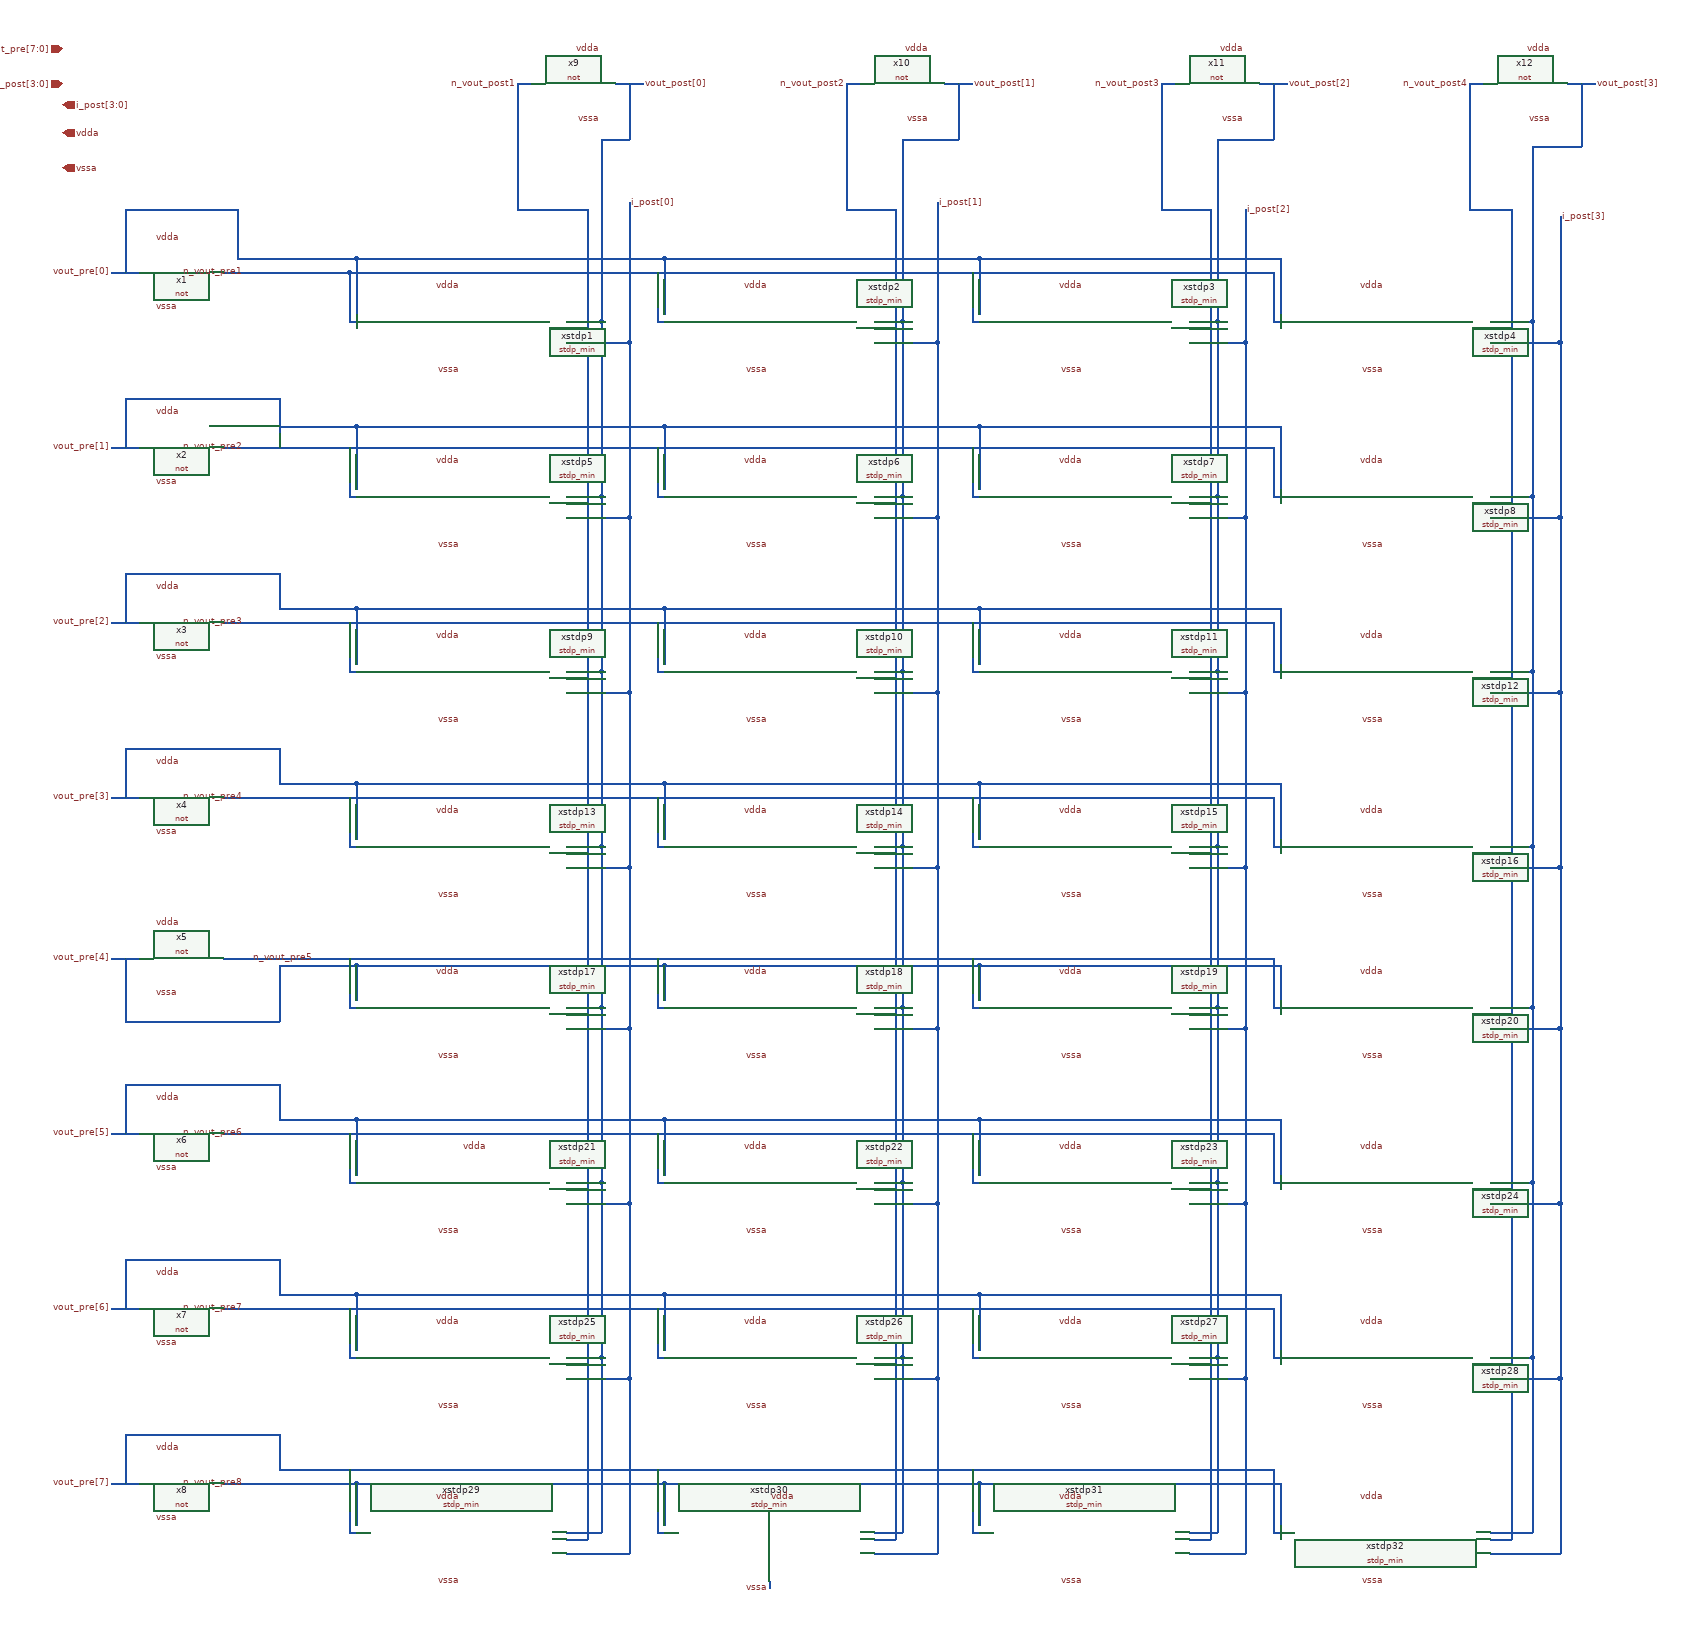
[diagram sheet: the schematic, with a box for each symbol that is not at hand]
v {xschem version=3.4.8RC file_version=1.3}
G {}
K {}
V {}
S {}
F {}
E {}
N 1130 110 1130 200 {
lab=n_vout_pre2}
N 700 110 1130 110 {
lab=n_vout_pre2}
N 1130 620 1130 700 {
lab=n_vout_pre4}
N 700 620 1130 620 {
lab=n_vout_pre4}
N 700 370 1130 370 {
lab=n_vout_pre3}
N 1130 370 1130 450 {
lab=n_vout_pre3}
N 700 110 700 200 {
lab=n_vout_pre2}
N 250 110 250 200 {
lab=n_vout_pre2}
N -190 110 -190 200 {
lab=n_vout_pre2}
N -190 370 -190 450 {
lab=n_vout_pre3}
N 250 370 250 450 {
lab=n_vout_pre3}
N 700 370 700 450 {
lab=n_vout_pre3}
N -190 620 -190 700 {
lab=n_vout_pre4}
N 250 620 250 700 {
lab=n_vout_pre4}
N 700 620 700 700 {
lab=n_vout_pre4}
N 160 460 160 710 {
lab=vout_post[0]}
N 110 710 160 710 {
lab=vout_post[0]}
N 110 460 160 460 {
lab=vout_post[0]}
N 110 210 160 210 {
lab=vout_post[0]}
N 110 -40 160 -40 {
lab=vout_post[0]}
N 590 460 590 710 {
lab=vout_post[1]}
N 550 710 590 710 {
lab=vout_post[1]}
N 550 460 590 460 {
lab=vout_post[1]}
N 550 210 590 210 {
lab=vout_post[1]}
N 550 -40 590 -40 {
lab=vout_post[1]}
N 1040 460 1040 710 {
lab=vout_post[2]}
N 1000 710 1040 710 {
lab=vout_post[2]}
N 1000 460 1040 460 {
lab=vout_post[2]}
N 1000 210 1040 210 {
lab=vout_post[2]}
N 1000 -40 1040 -40 {
lab=vout_post[2]}
N 1490 460 1490 710 {
lab=vout_post[3]}
N 1430 710 1490 710 {
lab=vout_post[3]}
N 1430 460 1490 460 {
lab=vout_post[3]}
N 1430 -40 1490 -40 {
lab=vout_post[3]}
N 200 490 200 740 {
lab=i_post[0]}
N 110 740 200 740 {
lab=i_post[0]}
N 110 -10 200 -10 {
lab=i_post[0]}
N 110 240 200 240 {
lab=i_post[0]}
N 110 490 200 490 {
lab=i_post[0]}
N 640 490 640 740 {
lab=i_post[1]}
N 550 740 640 740 {
lab=i_post[1]}
N 550 490 640 490 {
lab=i_post[1]}
N 550 240 640 240 {
lab=i_post[1]}
N 550 -10 640 -10 {
lab=i_post[1]}
N 1080 490 1080 740 {
lab=i_post[2]}
N 1000 740 1080 740 {
lab=i_post[2]}
N 1000 490 1080 490 {
lab=i_post[2]}
N 1000 240 1080 240 {
lab=i_post[2]}
N 1000 -10 1080 -10 {
lab=i_post[2]}
N 1530 490 1530 740 {
lab=i_post[3]}
N 1430 740 1530 740 {
lab=i_post[3]}
N 1430 490 1530 490 {
lab=i_post[3]}
N 1430 -10 1530 -10 {
lab=i_post[3]}
N 160 1440 160 1690 {
lab=vout_post[0]}
N 160 710 160 940 {
lab=vout_post[0]}
N 590 1440 590 1690 {
lab=vout_post[1]}
N 590 710 590 940 {
lab=vout_post[1]}
N 1040 1440 1040 1690 {
lab=vout_post[2]}
N 1040 710 1040 940 {
lab=vout_post[2]}
N 1490 1440 1490 1690 {
lab=vout_post[3]}
N 1490 710 1490 940 {
lab=vout_post[3]}
N 200 1470 200 1720 {
lab=i_post[0]}
N 110 1720 200 1720 {
lab=i_post[0]}
N 640 1470 640 1720 {
lab=i_post[1]}
N 1080 1470 1080 1720 {
lab=i_post[2]}
N 1530 1470 1530 1720 {
lab=i_post[3]}
N 110 940 160 940 {
lab=vout_post[0]}
N 110 970 200 970 {
lab=i_post[0]}
N 110 1190 160 1190 {
lab=vout_post[0]}
N 110 1220 200 1220 {
lab=i_post[0]}
N 110 1440 160 1440 {
lab=vout_post[0]}
N 110 1470 200 1470 {
lab=i_post[0]}
N 110 1690 160 1690 {
lab=vout_post[0]}
N 550 1690 590 1690 {
lab=vout_post[1]}
N 550 1720 640 1720 {
lab=i_post[1]}
N 550 1440 590 1440 {
lab=vout_post[1]}
N 550 1470 640 1470 {
lab=i_post[1]}
N 550 1190 590 1190 {
lab=vout_post[1]}
N 550 1220 640 1220 {
lab=i_post[1]}
N 550 940 590 940 {
lab=vout_post[1]}
N 550 970 640 970 {
lab=i_post[1]}
N 1000 940 1040 940 {
lab=vout_post[2]}
N 1000 970 1080 970 {
lab=i_post[2]}
N 1000 1190 1040 1190 {
lab=vout_post[2]}
N 1000 1220 1080 1220 {
lab=i_post[2]}
N 1000 1440 1040 1440 {
lab=vout_post[2]}
N 1000 1470 1080 1470 {
lab=i_post[2]}
N 1000 1690 1040 1690 {
lab=vout_post[2]}
N 1000 1720 1080 1720 {
lab=i_post[2]}
N 1430 1690 1490 1690 {
lab=vout_post[3]}
N 1430 1720 1530 1720 {
lab=i_post[3]}
N 1430 1440 1490 1440 {
lab=vout_post[3]}
N 1430 1470 1530 1470 {
lab=i_post[3]}
N 1430 1190 1490 1190 {
lab=vout_post[3]}
N 1430 1220 1530 1220 {
lab=i_post[3]}
N 1430 940 1490 940 {
lab=vout_post[3]}
N 1430 970 1530 970 {
lab=i_post[3]}
N 700 880 1130 880 {
lab=n_vout_pre5}
N -190 880 -190 930 {
lab=n_vout_pre5}
N 250 880 250 930 {
lab=n_vout_pre5}
N 700 880 700 930 {
lab=n_vout_pre5}
N 1130 880 1130 930 {
lab=n_vout_pre5}
N 700 1100 1130 1100 {
lab=n_vout_pre6}
N -190 1100 -190 1180 {
lab=n_vout_pre6}
N 250 1100 250 1180 {
lab=n_vout_pre6}
N 700 1100 700 1180 {
lab=n_vout_pre6}
N 1130 1100 1130 1180 {
lab=n_vout_pre6}
N 700 1350 1130 1350 {
lab=n_vout_pre7}
N -190 1350 -190 1430 {
lab=n_vout_pre7}
N 250 1350 250 1430 {
lab=n_vout_pre7}
N 700 1350 700 1430 {
lab=n_vout_pre7}
N 1130 1350 1130 1430 {
lab=n_vout_pre7}
N 700 1620 1130 1620 {
lab=n_vout_pre8}
N -190 1620 -190 1680 {
lab=n_vout_pre8}
N 250 1620 250 1680 {
lab=n_vout_pre8}
N 700 1620 700 1680 {
lab=n_vout_pre8}
N 1130 1620 1130 1680 {
lab=n_vout_pre8}
N 400 1760 400 1770 {
lab=vssa}
N 700 -130 1130 -130 {lab=vout_pre[0]}
N 1430 210 1490 210 {lab=vout_post[3]}
N 1430 240 1530 240 {lab=i_post[3]}
N -190 -130 250 -130 {lab=vout_pre[0]}
N 250 -130 700 -130 {lab=vout_pre[0]}
N 250 110 700 110 {
lab=n_vout_pre2}
N -190 110 250 110 {
lab=n_vout_pre2}
N -300 110 -190 110 {
lab=n_vout_pre2}
N -300 370 -190 370 {
lab=n_vout_pre3}
N -190 370 250 370 {
lab=n_vout_pre3}
N 250 370 700 370 {
lab=n_vout_pre3}
N -300 620 -190 620 {
lab=n_vout_pre4}
N -190 620 250 620 {
lab=n_vout_pre4}
N 250 620 700 620 {
lab=n_vout_pre4}
N 160 210 160 460 {
lab=vout_post[0]}
N 160 -40 160 210 {
lab=vout_post[0]}
N 160 -200 160 -40 {
lab=vout_post[0]}
N 590 210 590 460 {
lab=vout_post[1]}
N 590 -40 590 210 {
lab=vout_post[1]}
N 590 -200 590 -40 {
lab=vout_post[1]}
N 1040 210 1040 460 {
lab=vout_post[2]}
N 1040 -40 1040 210 {
lab=vout_post[2]}
N 1040 -190 1040 -40 {
lab=vout_post[2]}
N 1490 210 1490 460 {
lab=vout_post[3]}
N 1490 -180 1490 -40 {
lab=vout_post[3]}
N 200 -210 200 -10 {
lab=i_post[0]}
N 200 -10 200 240 {
lab=i_post[0]}
N 200 240 200 490 {
lab=i_post[0]}
N 640 240 640 490 {
lab=i_post[1]}
N 640 -10 640 240 {
lab=i_post[1]}
N 640 -210 640 -10 {
lab=i_post[1]}
N 1080 240 1080 490 {
lab=i_post[2]}
N 1080 -10 1080 240 {
lab=i_post[2]}
N 1080 -200 1080 -10 {
lab=i_post[2]}
N 1530 240 1530 490 {
lab=i_post[3]}
N 1530 -190 1530 -10 {
lab=i_post[3]}
N 200 740 200 970 {
lab=i_post[0]}
N 160 940 160 1190 {
lab=vout_post[0]}
N 200 970 200 1220 {
lab=i_post[0]}
N 160 1190 160 1440 {
lab=vout_post[0]}
N 200 1220 200 1470 {
lab=i_post[0]}
N 590 1190 590 1440 {
lab=vout_post[1]}
N 640 1220 640 1470 {
lab=i_post[1]}
N 590 940 590 1190 {
lab=vout_post[1]}
N 640 970 640 1220 {
lab=i_post[1]}
N 640 740 640 970 {
lab=i_post[1]}
N 1080 740 1080 970 {
lab=i_post[2]}
N 1040 940 1040 1190 {
lab=vout_post[2]}
N 1080 970 1080 1220 {
lab=i_post[2]}
N 1040 1190 1040 1440 {
lab=vout_post[2]}
N 1080 1220 1080 1470 {
lab=i_post[2]}
N 1490 1190 1490 1440 {
lab=vout_post[3]}
N 1530 1220 1530 1470 {
lab=i_post[3]}
N 1490 940 1490 1190 {
lab=vout_post[3]}
N 1530 970 1530 1220 {
lab=i_post[3]}
N 1530 740 1530 970 {
lab=i_post[3]}
N -300 880 -190 880 {
lab=n_vout_pre5}
N -190 880 250 880 {
lab=n_vout_pre5}
N 250 880 700 880 {
lab=n_vout_pre5}
N -300 1100 -190 1100 {
lab=n_vout_pre6}
N -190 1100 250 1100 {
lab=n_vout_pre6}
N 250 1100 700 1100 {
lab=n_vout_pre6}
N -300 1350 -190 1350 {
lab=n_vout_pre7}
N -190 1350 250 1350 {
lab=n_vout_pre7}
N 250 1350 700 1350 {
lab=n_vout_pre7}
N -300 1620 -190 1620 {
lab=n_vout_pre8}
N -190 1620 250 1620 {
lab=n_vout_pre8}
N 250 1620 700 1620 {
lab=n_vout_pre8}
N 1490 -40 1490 210 {
lab=vout_post[3]}
N 1530 -10 1530 240 {
lab=i_post[3]}
N -200 -110 -200 -40 {lab=vout_pre[0]}
N -200 -40 -190 -40 {lab=vout_pre[0]}
N 1120 -40 1130 -40 {lab=vout_pre[0]}
N 1120 -110 1120 -40 {lab=vout_pre[0]}
N 690 -40 700 -40 {lab=vout_pre[0]}
N 690 -110 690 -40 {lab=vout_pre[0]}
N 240 -40 250 -40 {lab=vout_pre[0]}
N 240 -110 240 -40 {lab=vout_pre[0]}
N -200 140 -200 210 {lab=n_vout_pre2}
N -200 210 -190 210 {lab=n_vout_pre2}
N -300 140 1120 140 {lab=n_vout_pre2}
N 1120 210 1130 210 {lab=n_vout_pre2}
N 1120 140 1120 210 {lab=n_vout_pre2}
N 690 210 700 210 {lab=n_vout_pre2}
N 690 140 690 210 {lab=n_vout_pre2}
N 240 210 250 210 {lab=n_vout_pre2}
N 240 140 240 210 {lab=n_vout_pre2}
N -200 390 -200 460 {lab=n_vout_pre3}
N -200 460 -190 460 {lab=n_vout_pre3}
N -300 390 1120 390 {lab=n_vout_pre3}
N 1120 460 1130 460 {lab=n_vout_pre3}
N 1120 390 1120 460 {lab=n_vout_pre3}
N 690 460 700 460 {lab=n_vout_pre3}
N 690 390 690 460 {lab=n_vout_pre3}
N 240 460 250 460 {lab=n_vout_pre3}
N 240 390 240 460 {lab=n_vout_pre3}
N -200 640 -200 710 {lab=n_vout_pre4}
N -200 710 -190 710 {lab=n_vout_pre4}
N -300 640 1120 640 {lab=n_vout_pre4}
N 1120 710 1130 710 {lab=n_vout_pre4}
N 1120 640 1120 710 {lab=n_vout_pre4}
N 690 710 700 710 {lab=n_vout_pre4}
N 690 640 690 710 {lab=n_vout_pre4}
N 240 710 250 710 {lab=n_vout_pre4}
N 240 640 240 710 {lab=n_vout_pre4}
N -200 870 -200 940 {lab=n_vout_pre5}
N -200 940 -190 940 {lab=n_vout_pre5}
N -300 870 1120 870 {lab=n_vout_pre5}
N 1120 940 1130 940 {lab=n_vout_pre5}
N 1120 870 1120 940 {lab=n_vout_pre5}
N 690 940 700 940 {lab=n_vout_pre5}
N 690 870 690 940 {lab=n_vout_pre5}
N 240 940 250 940 {lab=n_vout_pre5}
N 240 870 240 940 {lab=n_vout_pre5}
N -200 1120 -200 1190 {lab=n_vout_pre6}
N -200 1190 -190 1190 {lab=n_vout_pre6}
N -300 1120 1120 1120 {lab=n_vout_pre6}
N 1120 1190 1130 1190 {lab=n_vout_pre6}
N 1120 1120 1120 1190 {lab=n_vout_pre6}
N 690 1190 700 1190 {lab=n_vout_pre6}
N 690 1120 690 1190 {lab=n_vout_pre6}
N 240 1190 250 1190 {lab=n_vout_pre6}
N 240 1120 240 1190 {lab=n_vout_pre6}
N -200 1370 -200 1440 {lab=n_vout_pre7}
N -200 1440 -190 1440 {lab=n_vout_pre7}
N -300 1370 1120 1370 {lab=n_vout_pre7}
N 1120 1440 1130 1440 {lab=n_vout_pre7}
N 1120 1370 1120 1440 {lab=n_vout_pre7}
N 690 1440 700 1440 {lab=n_vout_pre7}
N 690 1370 690 1440 {lab=n_vout_pre7}
N 240 1440 250 1440 {lab=n_vout_pre7}
N 240 1370 240 1440 {lab=n_vout_pre7}
N -300 1600 1120 1600 {lab=n_vout_pre8}
N -200 1690 -190 1690 {lab=n_vout_pre8}
N -200 1640 -200 1690 {lab=n_vout_pre8}
N 240 1690 250 1690 {lab=n_vout_pre8}
N -200 1600 -200 1640 {lab=n_vout_pre8}
N 240 1600 240 1690 {lab=n_vout_pre8}
N 690 1690 700 1690 {lab=n_vout_pre8}
N 690 1600 690 1690 {lab=n_vout_pre8}
N 1120 1690 1130 1690 {lab=n_vout_pre8}
N 1120 1600 1120 1690 {lab=n_vout_pre8}
N -540 -110 -500 -110 {lab=vout_pre[0]}
N -380 -110 -350 -110 {lab=vout_pre[0]}
N -540 140 -500 140 {lab=n_vout_pre2}
N -380 140 -350 140 {lab=n_vout_pre2}
N -350 140 -300 140 {lab=n_vout_pre2}
N -520 70 -520 140 {lab=n_vout_pre2}
N -300 70 -300 120 {lab=n_vout_pre2}
N -520 70 -300 70 {lab=n_vout_pre2}
N -540 390 -500 390 {lab=n_vout_pre3}
N -380 390 -350 390 {lab=n_vout_pre3}
N -350 390 -300 390 {lab=n_vout_pre3}
N -520 320 -520 390 {lab=n_vout_pre3}
N -520 320 -300 320 {lab=n_vout_pre3}
N -300 320 -300 370 {lab=n_vout_pre3}
N -540 640 -500 640 {lab=n_vout_pre4}
N -380 640 -350 640 {lab=n_vout_pre4}
N -520 570 -520 640 {lab=n_vout_pre4}
N -520 570 -300 570 {lab=n_vout_pre4}
N -300 570 -300 620 {lab=n_vout_pre4}
N -350 640 -300 640 {lab=n_vout_pre4}
N -540 870 -500 870 {lab=n_vout_pre5}
N -380 870 -350 870 {lab=n_vout_pre5}
N -350 870 -300 870 {lab=n_vout_pre5}
N -300 880 -300 960 {lab=n_vout_pre5}
N -520 960 -300 960 {lab=n_vout_pre5}
N -520 870 -520 960 {lab=n_vout_pre5}
N -540 1120 -500 1120 {lab=n_vout_pre6}
N -380 1120 -350 1120 {lab=n_vout_pre6}
N -520 1050 -520 1120 {lab=n_vout_pre6}
N -520 1050 -300 1050 {lab=n_vout_pre6}
N -350 1120 -300 1120 {lab=n_vout_pre6}
N -300 1050 -300 1100 {lab=n_vout_pre6}
N -540 1370 -500 1370 {lab=n_vout_pre7}
N -380 1370 -350 1370 {lab=n_vout_pre7}
N -520 1300 -520 1370 {lab=n_vout_pre7}
N -520 1300 -300 1300 {lab=n_vout_pre7}
N -350 1370 -300 1370 {lab=n_vout_pre7}
N -300 1300 -300 1350 {lab=n_vout_pre7}
N -540 1620 -500 1620 {lab=n_vout_pre8}
N -380 1620 -350 1620 {lab=n_vout_pre8}
N -520 1550 -520 1620 {lab=n_vout_pre8}
N -520 1550 -300 1550 {lab=n_vout_pre8}
N -350 1620 -300 1620 {lab=n_vout_pre8}
N -300 1550 -300 1600 {lab=n_vout_pre8}
N 140 -200 140 1700 {lab=n_vout_post1}
N 110 1700 140 1700 {lab=n_vout_post1}
N 110 1450 140 1450 {lab=n_vout_post1}
N 110 1200 140 1200 {lab=n_vout_post1}
N 110 950 140 950 {lab=n_vout_post1}
N 110 720 140 720 {lab=n_vout_post1}
N 110 470 140 470 {lab=n_vout_post1}
N 110 220 140 220 {lab=n_vout_post1}
N 110 -30 140 -30 {lab=n_vout_post1}
N 580 -200 580 1700 {lab=n_vout_post2}
N 550 1700 580 1700 {lab=n_vout_post2}
N 550 1450 580 1450 {lab=n_vout_post2}
N 550 1200 580 1200 {lab=n_vout_post2}
N 550 950 580 950 {lab=n_vout_post2}
N 550 720 580 720 {lab=n_vout_post2}
N 550 470 580 470 {lab=n_vout_post2}
N 550 220 580 220 {lab=n_vout_post2}
N 550 -30 580 -30 {lab=n_vout_post2}
N 1030 -200 1030 1700 {lab=n_vout_post3}
N 1000 1700 1030 1700 {lab=n_vout_post3}
N 1000 1450 1030 1450 {lab=n_vout_post3}
N 1000 1200 1030 1200 {lab=n_vout_post3}
N 1000 950 1030 950 {lab=n_vout_post3}
N 1000 720 1030 720 {lab=n_vout_post3}
N 1000 470 1030 470 {lab=n_vout_post3}
N 1000 220 1030 220 {lab=n_vout_post3}
N 1000 -30 1030 -30 {lab=n_vout_post3}
N 1460 -200 1460 1700 {lab=n_vout_post4}
N 1430 1700 1460 1700 {lab=n_vout_post4}
N 1430 1450 1460 1450 {lab=n_vout_post4}
N 1430 1200 1460 1200 {lab=n_vout_post4}
N 1430 950 1460 950 {lab=n_vout_post4}
N 1430 720 1460 720 {lab=n_vout_post4}
N 1430 470 1460 470 {lab=n_vout_post4}
N 1430 220 1460 220 {lab=n_vout_post4}
N 1430 -30 1460 -30 {lab=n_vout_post4}
N 180 -380 220 -380 {lab=vout_post[0]}
N 40 -380 60 -380 {lab=n_vout_post1}
N 40 -380 40 -200 {lab=n_vout_post1}
N 40 -200 140 -200 {lab=n_vout_post1}
N 160 -300 160 -200 {lab=vout_post[0]}
N 160 -300 200 -300 {lab=vout_post[0]}
N 200 -380 200 -300 {lab=vout_post[0]}
N 650 -380 690 -380 {lab=vout_post[1]}
N 510 -380 530 -380 {lab=n_vout_post2}
N 510 -380 510 -200 {lab=n_vout_post2}
N 670 -380 670 -300 {lab=vout_post[1]}
N 590 -300 670 -300 {lab=vout_post[1]}
N 590 -300 590 -200 {lab=vout_post[1]}
N 510 -200 580 -200 {lab=n_vout_post2}
N 1100 -380 1140 -380 {lab=vout_post[2]}
N 960 -380 980 -380 {lab=n_vout_post3}
N 960 -380 960 -200 {lab=n_vout_post3}
N 1120 -380 1120 -300 {lab=vout_post[2]}
N 960 -200 1030 -200 {lab=n_vout_post3}
N 1040 -300 1040 -190 {lab=vout_post[2]}
N 1040 -300 1120 -300 {lab=vout_post[2]}
N 1540 -380 1580 -380 {lab=vout_post[3]}
N 1400 -380 1420 -380 {lab=n_vout_post4}
N 1400 -380 1400 -200 {lab=n_vout_post4}
N 1560 -380 1560 -300 {lab=vout_post[3]}
N 1410 -200 1460 -200 {lab=n_vout_post4}
N 1490 -290 1490 -180 {lab=vout_post[3]}
N 1490 -290 1560 -290 {lab=vout_post[3]}
N 1560 -300 1560 -290 {lab=vout_post[3]}
N 1400 -200 1410 -200 {lab=n_vout_post4}
N -190 -130 -190 -50 {lab=vout_pre[0]}
N -200 -110 1120 -110 {lab=vout_pre[0]}
N 250 -130 250 -50 {lab=vout_pre[0]}
N 700 -130 700 -50 {lab=vout_pre[0]}
N 1130 -130 1130 -50 {lab=vout_pre[0]}
N -350 -110 -200 -110 {lab=vout_pre[0]}
N -360 -130 -190 -130 {lab=vout_pre[0]}
N -360 -200 -360 -130 {lab=vout_pre[0]}
N -520 -200 -360 -200 {lab=vout_pre[0]}
N -520 -200 -520 -110 {lab=vout_pre[0]}
C {devices/lab_pin.sym} -540 -110 0 0 {name=p1 lab=vout_pre[0]}
C {devices/iopin.sym} -610 -310 0 1 {name=p7 lab=vdda}
C {devices/iopin.sym} -610 -260 0 1 {name=p8 lab=vssa}
C {Synapse/stdp_min.sym} 400 -50 0 0 {name=xstdp2}
C {Synapse/stdp_min.sym} 850 -50 0 0 {name=xstdp3}
C {Synapse/stdp_min.sym} 1280 -50 0 0 {name=xstdp4}
C {devices/lab_pin.sym} 200 -210 0 1 {name=p9 lab=i_post[0]}
C {Synapse/stdp_min.sym} -40 200 0 0 {name=xstdp5}
C {Synapse/stdp_min.sym} 400 200 0 0 {name=xstdp6}
C {Synapse/stdp_min.sym} 850 200 0 0 {name=xstdp7}
C {Synapse/stdp_min.sym} 1280 200 0 0 {name=xstdp8}
C {Synapse/stdp_min.sym} -40 450 0 0 {name=xstdp9}
C {Synapse/stdp_min.sym} 400 450 0 0 {name=xstdp10}
C {Synapse/stdp_min.sym} 850 450 0 0 {name=xstdp11}
C {Synapse/stdp_min.sym} 1280 450 0 0 {name=xstdp12}
C {Synapse/stdp_min.sym} -40 700 0 0 {name=xstdp13}
C {Synapse/stdp_min.sym} 400 700 0 0 {name=xstdp14}
C {Synapse/stdp_min.sym} 850 700 0 0 {name=xstdp15}
C {Synapse/stdp_min.sym} 1280 700 0 0 {name=xstdp16}
C {devices/lab_pin.sym} -40 -90 1 0 {name=p20 sig_type=std_logic lab=vdda}
C {devices/lab_pin.sym} -40 160 1 0 {name=p21 sig_type=std_logic lab=vdda}
C {devices/lab_pin.sym} -40 410 1 0 {name=p22 sig_type=std_logic lab=vdda}
C {devices/lab_pin.sym} -40 660 1 0 {name=p23 sig_type=std_logic lab=vdda}
C {devices/lab_pin.sym} 400 -90 1 0 {name=p24 sig_type=std_logic lab=vdda}
C {devices/lab_pin.sym} 400 160 1 0 {name=p25 sig_type=std_logic lab=vdda}
C {devices/lab_pin.sym} 400 410 1 0 {name=p26 sig_type=std_logic lab=vdda}
C {devices/lab_pin.sym} 400 660 1 0 {name=p27 sig_type=std_logic lab=vdda}
C {devices/lab_pin.sym} 850 -90 1 0 {name=p28 sig_type=std_logic lab=vdda}
C {devices/lab_pin.sym} 850 160 1 0 {name=p29 sig_type=std_logic lab=vdda}
C {devices/lab_pin.sym} 850 410 1 0 {name=p30 sig_type=std_logic lab=vdda}
C {devices/lab_pin.sym} 850 660 1 0 {name=p31 sig_type=std_logic lab=vdda}
C {devices/lab_pin.sym} 1280 -90 1 0 {name=p32 sig_type=std_logic lab=vdda}
C {devices/lab_pin.sym} 1280 160 1 0 {name=p33 sig_type=std_logic lab=vdda}
C {devices/lab_pin.sym} 1280 410 1 0 {name=p34 sig_type=std_logic lab=vdda}
C {devices/lab_pin.sym} 1280 660 1 0 {name=p35 sig_type=std_logic lab=vdda}
C {devices/lab_pin.sym} -40 30 3 0 {name=p36 sig_type=std_logic lab=vssa}
C {devices/lab_pin.sym} -40 280 3 0 {name=p37 sig_type=std_logic lab=vssa}
C {devices/lab_pin.sym} -40 530 3 0 {name=p38 sig_type=std_logic lab=vssa}
C {devices/lab_pin.sym} -40 780 3 0 {name=p39 sig_type=std_logic lab=vssa}
C {devices/lab_pin.sym} 400 30 3 0 {name=p40 sig_type=std_logic lab=vssa}
C {devices/lab_pin.sym} 400 280 3 0 {name=p41 sig_type=std_logic lab=vssa}
C {devices/lab_pin.sym} 400 530 3 0 {name=p42 sig_type=std_logic lab=vssa}
C {devices/lab_pin.sym} 400 780 3 0 {name=p43 sig_type=std_logic lab=vssa}
C {devices/lab_pin.sym} 850 30 3 0 {name=p44 sig_type=std_logic lab=vssa}
C {devices/lab_pin.sym} 850 280 3 0 {name=p45 sig_type=std_logic lab=vssa}
C {devices/lab_pin.sym} 850 530 3 0 {name=p46 sig_type=std_logic lab=vssa}
C {devices/lab_pin.sym} 850 780 3 0 {name=p47 sig_type=std_logic lab=vssa}
C {devices/lab_pin.sym} 1280 30 3 0 {name=p48 sig_type=std_logic lab=vssa}
C {devices/lab_pin.sym} 1280 280 3 0 {name=p49 sig_type=std_logic lab=vssa}
C {devices/lab_pin.sym} 1280 530 3 0 {name=p50 sig_type=std_logic lab=vssa}
C {devices/lab_pin.sym} 1280 780 3 0 {name=p51 sig_type=std_logic lab=vssa}
C {Synapse/stdp_min.sym} -40 930 0 0 {name=xstdp17}
C {Synapse/stdp_min.sym} 400 930 0 0 {name=xstdp18}
C {Synapse/stdp_min.sym} 850 930 0 0 {name=xstdp19}
C {Synapse/stdp_min.sym} 1280 930 0 0 {name=xstdp20}
C {Synapse/stdp_min.sym} -40 1180 0 0 {name=xstdp21}
C {Synapse/stdp_min.sym} 400 1180 0 0 {name=xstdp22}
C {Synapse/stdp_min.sym} 850 1180 0 0 {name=xstdp23}
C {Synapse/stdp_min.sym} 1280 1180 0 0 {name=xstdp24}
C {Synapse/stdp_min.sym} -40 1430 0 0 {name=xstdp25}
C {Synapse/stdp_min.sym} 400 1430 0 0 {name=xstdp26}
C {Synapse/stdp_min.sym} 850 1430 0 0 {name=xstdp27}
C {Synapse/stdp_min.sym} 1280 1430 0 0 {name=xstdp28}
C {Synapse/stdp_min.sym} -40 1680 0 0 {name=xstdp29}
C {Synapse/stdp_min.sym} 400 1680 0 0 {name=xstdp30}
C {Synapse/stdp_min.sym} 850 1680 0 0 {name=xstdp31}
C {Synapse/stdp_min.sym} 1280 1680 0 0 {name=xstdp32}
C {devices/lab_pin.sym} 1280 1010 3 0 {name=p53 sig_type=std_logic lab=vssa}
C {devices/lab_pin.sym} 1280 1260 3 0 {name=p55 sig_type=std_logic lab=vssa}
C {devices/lab_pin.sym} 1280 1510 3 0 {name=p56 sig_type=std_logic lab=vssa}
C {devices/lab_pin.sym} 1280 1760 3 0 {name=p57 sig_type=std_logic lab=vssa}
C {devices/lab_pin.sym} 850 1510 3 0 {name=p58 sig_type=std_logic lab=vssa}
C {devices/lab_pin.sym} 850 1760 3 0 {name=p59 sig_type=std_logic lab=vssa}
C {devices/lab_pin.sym} 850 1010 3 0 {name=p60 sig_type=std_logic lab=vssa}
C {devices/lab_pin.sym} 850 1260 3 0 {name=p61 sig_type=std_logic lab=vssa}
C {devices/lab_pin.sym} -40 890 1 0 {name=p66 sig_type=std_logic lab=vdda}
C {devices/lab_pin.sym} 400 890 1 0 {name=p67 sig_type=std_logic lab=vdda}
C {devices/lab_pin.sym} 850 890 1 0 {name=p68 sig_type=std_logic lab=vdda}
C {devices/lab_pin.sym} 1280 890 1 0 {name=p69 sig_type=std_logic lab=vdda}
C {devices/lab_pin.sym} -40 1140 2 0 {name=p70 sig_type=std_logic lab=vdda}
C {devices/lab_pin.sym} 400 1140 1 0 {name=p71 sig_type=std_logic lab=vdda}
C {devices/lab_pin.sym} 850 1140 1 0 {name=p72 sig_type=std_logic lab=vdda}
C {devices/lab_pin.sym} -40 1390 1 0 {name=p73 sig_type=std_logic lab=vdda}
C {devices/lab_pin.sym} 400 1390 1 0 {name=p74 sig_type=std_logic lab=vdda}
C {devices/lab_pin.sym} 850 1390 1 0 {name=p75 sig_type=std_logic lab=vdda}
C {devices/lab_pin.sym} -40 1640 1 0 {name=p76 sig_type=std_logic lab=vdda}
C {devices/lab_pin.sym} 400 1640 2 0 {name=p77 sig_type=std_logic lab=vdda}
C {devices/lab_pin.sym} 850 1640 1 0 {name=p78 sig_type=std_logic lab=vdda}
C {devices/lab_pin.sym} 1280 1140 1 0 {name=p79 sig_type=std_logic lab=vdda}
C {devices/lab_pin.sym} 1280 1390 1 0 {name=p80 sig_type=std_logic lab=vdda}
C {devices/lab_pin.sym} 1280 1640 1 0 {name=p81 sig_type=std_logic lab=vdda}
C {devices/lab_pin.sym} -40 1010 3 0 {name=p86 sig_type=std_logic lab=vssa}
C {devices/lab_pin.sym} -40 1260 0 0 {name=p87 sig_type=std_logic lab=vssa}
C {devices/lab_pin.sym} -40 1510 3 0 {name=p88 sig_type=std_logic lab=vssa}
C {devices/lab_pin.sym} -40 1760 3 0 {name=p89 sig_type=std_logic lab=vssa}
C {devices/lab_pin.sym} 400 1510 3 0 {name=p90 sig_type=std_logic lab=vssa}
C {devices/lab_pin.sym} 400 1770 0 0 {name=p91 sig_type=std_logic lab=vssa}
C {devices/lab_pin.sym} 400 1010 3 0 {name=p92 sig_type=std_logic lab=vssa}
C {devices/lab_pin.sym} 400 1260 3 0 {name=p93 sig_type=std_logic lab=vssa}
C {Synapse/stdp_min.sym} -40 -50 0 0 {name=xstdp1}
C {devices/lab_pin.sym} -250 870 1 0 {name=p15 lab=n_vout_pre5}
C {not.sym} -480 -80 0 0 {name=x1}
C {devices/lab_pin.sym} -480 -160 2 0 {name=p65 sig_type=std_logic lab=vdda}
C {devices/lab_pin.sym} -480 -60 0 1 {name=p94 sig_type=std_logic lab=vssa}
C {devices/lab_pin.sym} -350 140 3 0 {name=p95 lab=n_vout_pre2}
C {not.sym} -480 170 0 0 {name=x2}
C {devices/lab_pin.sym} -480 90 2 0 {name=p96 sig_type=std_logic lab=vdda}
C {devices/lab_pin.sym} -480 190 0 1 {name=p97 sig_type=std_logic lab=vssa}
C {devices/lab_pin.sym} -350 390 3 0 {name=p13 lab=n_vout_pre3}
C {not.sym} -480 420 0 0 {name=x3}
C {devices/lab_pin.sym} -480 340 2 0 {name=p98 sig_type=std_logic lab=vdda}
C {devices/lab_pin.sym} -480 440 0 1 {name=p99 sig_type=std_logic lab=vssa}
C {devices/lab_pin.sym} -350 640 3 0 {name=p100 lab=n_vout_pre4}
C {not.sym} -480 670 0 0 {name=x4}
C {devices/lab_pin.sym} -480 590 2 0 {name=p101 sig_type=std_logic lab=vdda}
C {devices/lab_pin.sym} -480 690 0 1 {name=p102 sig_type=std_logic lab=vssa}
C {not.sym} -480 900 0 0 {name=x5}
C {devices/lab_pin.sym} -480 820 2 0 {name=p103 sig_type=std_logic lab=vdda}
C {devices/lab_pin.sym} -480 920 0 1 {name=p104 sig_type=std_logic lab=vssa}
C {devices/lab_pin.sym} -350 1120 3 0 {name=p14 lab=n_vout_pre6}
C {not.sym} -480 1150 0 0 {name=x6}
C {devices/lab_pin.sym} -480 1070 2 0 {name=p105 sig_type=std_logic lab=vdda}
C {devices/lab_pin.sym} -480 1170 0 1 {name=p106 sig_type=std_logic lab=vssa}
C {devices/lab_pin.sym} -350 1370 3 0 {name=p62 lab=n_vout_pre7}
C {not.sym} -480 1400 0 0 {name=x7}
C {devices/lab_pin.sym} -480 1320 2 0 {name=p107 sig_type=std_logic lab=vdda}
C {devices/lab_pin.sym} -480 1420 0 1 {name=p108 sig_type=std_logic lab=vssa}
C {devices/lab_pin.sym} -350 1620 3 0 {name=p84 lab=n_vout_pre8}
C {not.sym} -480 1650 0 0 {name=x8}
C {devices/lab_pin.sym} -480 1570 2 0 {name=p109 sig_type=std_logic lab=vdda}
C {devices/lab_pin.sym} -480 1670 0 1 {name=p110 sig_type=std_logic lab=vssa}
C {not.sym} 160 -350 0 1 {name=x9}
C {devices/lab_pin.sym} 160 -430 2 1 {name=p85 sig_type=std_logic lab=vdda}
C {devices/lab_pin.sym} 160 -330 0 0 {name=p111 sig_type=std_logic lab=vssa}
C {devices/lab_pin.sym} 220 -380 0 1 {name=p64 lab=vout_post[0]}
C {devices/lab_pin.sym} 40 -380 0 0 {name=p5 lab=n_vout_post1}
C {not.sym} 630 -350 0 1 {name=x10}
C {devices/lab_pin.sym} 630 -330 0 0 {name=p112 sig_type=std_logic lab=vssa}
C {devices/lab_pin.sym} 510 -380 0 0 {name=p114 lab=n_vout_post2}
C {devices/lab_pin.sym} 630 -430 2 1 {name=p113 sig_type=std_logic lab=vdda}
C {not.sym} 1080 -350 0 1 {name=x11}
C {devices/lab_pin.sym} 1080 -330 0 0 {name=p116 sig_type=std_logic lab=vssa}
C {devices/lab_pin.sym} 960 -380 0 0 {name=p117 lab=n_vout_post3}
C {devices/lab_pin.sym} 1080 -430 2 1 {name=p118 sig_type=std_logic lab=vdda}
C {not.sym} 1520 -350 0 1 {name=x12}
C {devices/lab_pin.sym} 1520 -330 0 0 {name=p119 sig_type=std_logic lab=vssa}
C {devices/lab_pin.sym} 1400 -380 0 0 {name=p120 lab=n_vout_post4}
C {devices/lab_pin.sym} 1520 -430 2 1 {name=p121 sig_type=std_logic lab=vdda}
C {devices/iopin.sym} -610 -430 0 0 {name=p17 lab=vout_pre[7:0]}
C {devices/lab_pin.sym} -540 140 0 0 {name=p52 lab=vout_pre[1]}
C {devices/lab_pin.sym} -540 390 0 0 {name=p2 lab=vout_pre[2]}
C {devices/lab_pin.sym} -540 640 0 0 {name=p3 lab=vout_pre[3]}
C {devices/lab_pin.sym} -540 870 0 0 {name=p4 lab=vout_pre[4]}
C {devices/lab_pin.sym} -540 1120 0 0 {name=p54 lab=vout_pre[5]}
C {devices/lab_pin.sym} -540 1370 0 0 {name=p82 lab=vout_pre[6]}
C {devices/lab_pin.sym} -540 1620 0 0 {name=p10 lab=vout_pre[7]}
C {devices/iopin.sym} -610 -380 0 0 {name=p63 lab=vout_post[3:0]}
C {devices/lab_pin.sym} 690 -380 0 1 {name=p16 lab=vout_post[1]}
C {devices/lab_pin.sym} 1140 -380 0 1 {name=p83 lab=vout_post[2]}
C {devices/lab_pin.sym} 1580 -380 0 1 {name=p18 lab=vout_post[3]}
C {devices/iopin.sym} -610 -350 0 1 {name=p115 lab=i_post[3:0]}
C {devices/lab_pin.sym} 640 -210 0 1 {name=p19 lab=i_post[1]}
C {devices/lab_pin.sym} 1080 -200 0 1 {name=p122 lab=i_post[2]}
C {devices/lab_pin.sym} 1530 -190 0 1 {name=p11 lab=i_post[3]}
C {devices/lab_pin.sym} -350 -110 3 0 {name=p6 lab=n_vout_pre1}
